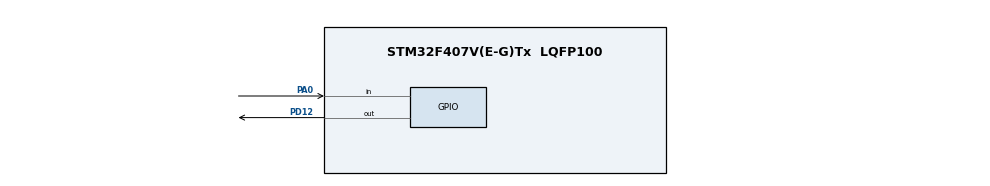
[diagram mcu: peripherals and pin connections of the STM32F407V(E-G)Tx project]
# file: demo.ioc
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Mcu.Family=STM32F4
Mcu.Name=STM32F407V(E-G)Tx
Mcu.Package=LQFP100
NVIC.PriorityGroup=NVIC_PRIORITYGROUP_4
PA0-WKUP.Signal=GPIO_Input
PD12.Signal=GPIO_Output
ProjectManager.HeapSize=0x200
ProjectManager.StackSize=0x400
ProjectManager.TargetToolchain=TrueSTUDIO
RCC.48MHZClocksFreq_Value=84000000
RCC.AHBFreq_Value=168000000
RCC.APB1CLKDivider=RCC_HCLK_DIV4
RCC.APB1Freq_Value=42000000
RCC.APB1TimFreq_Value=84000000
RCC.APB2CLKDivider=RCC_HCLK_DIV4
RCC.APB2Freq_Value=42000000
RCC.APB2TimFreq_Value=84000000
RCC.CortexFreq_Value=168000000
RCC.HCLKFreq_Value=168000000
RCC.HSE_VALUE=25000000
RCC.HSI_VALUE=16000000
RCC.LSE_VALUE=32768
RCC.PLLM=8
RCC.PLLN=168
RCC.SYSCLKFreq_VALUE=168000000
RCC.SYSCLKSource=RCC_SYSCLKSOURCE_PLLCLK
RCC.VCOOutputFreq_Value=336000000
board=demo

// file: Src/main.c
/**
  ******************************************************************************
  * File Name          : main.c
  * Description        : Main program body
  ******************************************************************************
  ** This notice applies to any and all portions of this file
  * that are not between comment pairs USER CODE BEGIN and
  * USER CODE END. Other portions of this file, whether
  * inserted by the user or by software development tools
  * are owned by their respective copyright owners.
  *
  * COPYRIGHT(c) 2018 STMicroelectronics
  *
  * Redistribution and use in source and binary forms, with or without modification,
  * are permitted provided that the following conditions are met:
  *   1. Redistributions of source code must retain the above copyright notice,
  *      this list of conditions and the following disclaimer.
  *   2. Redistributions in binary form must reproduce the above copyright notice,
  *      this list of conditions and the following disclaimer in the documentation
  *      and/or other materials provided with the distribution.
  *   3. Neither the name of STMicroelectronics nor the names of its contributors
  *      may be used to endorse or promote products derived from this software
  *      without specific prior written permission.
  *
  * THIS SOFTWARE IS PROVIDED BY THE COPYRIGHT HOLDERS AND CONTRIBUTORS "AS IS"
  * AND ANY EXPRESS OR IMPLIED WARRANTIES, INCLUDING, BUT NOT LIMITED TO, THE
  * IMPLIED WARRANTIES OF MERCHANTABILITY AND FITNESS FOR A PARTICULAR PURPOSE ARE
  * DISCLAIMED. IN NO EVENT SHALL THE COPYRIGHT HOLDER OR CONTRIBUTORS BE LIABLE
  * FOR ANY DIRECT, INDIRECT, INCIDENTAL, SPECIAL, EXEMPLARY, OR CONSEQUENTIAL
  * DAMAGES (INCLUDING, BUT NOT LIMITED TO, PROCUREMENT OF SUBSTITUTE GOODS OR
  * SERVICES; LOSS OF USE, DATA, OR PROFITS; OR BUSINESS INTERRUPTION) HOWEVER
  * CAUSED AND ON ANY THEORY OF LIABILITY, WHETHER IN CONTRACT, STRICT LIABILITY,
  * OR TORT (INCLUDING NEGLIGENCE OR OTHERWISE) ARISING IN ANY WAY OUT OF THE USE
  * OF THIS SOFTWARE, EVEN IF ADVISED OF THE POSSIBILITY OF SUCH DAMAGE.
  *
  ******************************************************************************
  */

#include "main.h"
#include "stm32f4xx_hal.h"

/* USER CODE BEGIN PV */
/* Private variables ---------------------------------------------------------*/

/* USER CODE END PV */

void SystemClock_Config(void);
static void MX_GPIO_Init(void);

/* USER CODE BEGIN PFP */
/* Private function prototypes -----------------------------------------------*/

/* USER CODE END PFP */

/* USER CODE BEGIN 0 */

void delay(uint16_t time_delay)
{
	volatile int i=0;
    for( i=0; i<time_delay;i++)
    {

    }
}

int v_counter=1;
int v_toggle;
int v_dir=1;
/* USER CODE END 0 */

int main(void)
{

  /* MCU Configuration----------------------------------------------------------*/

  /* Reset of all peripherals, Initializes the Flash interface and the Systick. */
  HAL_Init();

  /* Configure the system clock */
  SystemClock_Config();

  /* Initialize all configured peripherals */
  MX_GPIO_Init();

  /* Infinite loop */
  while (1)
  {

  /* USER CODE BEGIN 3 */
	 //// HAL_GPIO_TogglePin(GPIOD, GPIO_PIN_12);
		 // delay(599);
	  if(HAL_GPIO_ReadPin(GPIOA, GPIO_PIN_0))
	  {
		v_toggle=1;
	  }
	  else if(v_toggle)
	  {
		  // HAL_Delay(1000);
		   if(v_counter>8 || v_counter<2)
		   {
			   v_dir=-(v_dir);
		   }
		   v_counter= v_counter + v_dir;
		   v_toggle=0;
	  }

		 HAL_GPIO_WritePin(GPIOD, GPIO_PIN_12,GPIO_PIN_SET);
		 		  delay(119*(v_counter));
			  HAL_GPIO_WritePin(GPIOD, GPIO_PIN_12,GPIO_PIN_RESET);
			  delay(119*(10-v_counter));
  }
  /* USER CODE END 3 */

}

/** System Clock Configuration
*/
void SystemClock_Config(void)
{

  RCC_OscInitTypeDef RCC_OscInitStruct;
  RCC_ClkInitTypeDef RCC_ClkInitStruct;

    /**Configure the main internal regulator output voltage
    */
  __HAL_RCC_PWR_CLK_ENABLE();

  __HAL_PWR_VOLTAGESCALING_CONFIG(PWR_REGULATOR_VOLTAGE_SCALE1);

    /**Initializes the CPU, AHB and APB busses clocks
    */
  RCC_OscInitStruct.OscillatorType = RCC_OSCILLATORTYPE_HSI;
  RCC_OscInitStruct.HSIState = RCC_HSI_ON;
  RCC_OscInitStruct.HSICalibrationValue = 16;
  RCC_OscInitStruct.PLL.PLLState = RCC_PLL_ON;
  RCC_OscInitStruct.PLL.PLLSource = RCC_PLLSOURCE_HSI;
  RCC_OscInitStruct.PLL.PLLM = 8;
  RCC_OscInitStruct.PLL.PLLN = 168;
  RCC_OscInitStruct.PLL.PLLP = RCC_PLLP_DIV2;
  RCC_OscInitStruct.PLL.PLLQ = 4;
  if (HAL_RCC_OscConfig(&RCC_OscInitStruct) != HAL_OK)
  {
    _Error_Handler(__FILE__, __LINE__);
  }

    /**Initializes the CPU, AHB and APB busses clocks
    */
  RCC_ClkInitStruct.ClockType = RCC_CLOCKTYPE_HCLK|RCC_CLOCKTYPE_SYSCLK
                              |RCC_CLOCKTYPE_PCLK1|RCC_CLOCKTYPE_PCLK2;
  RCC_ClkInitStruct.SYSCLKSource = RCC_SYSCLKSOURCE_PLLCLK;
  RCC_ClkInitStruct.AHBCLKDivider = RCC_SYSCLK_DIV1;
  RCC_ClkInitStruct.APB1CLKDivider = RCC_HCLK_DIV8;
  RCC_ClkInitStruct.APB2CLKDivider = RCC_HCLK_DIV4;

  if (HAL_RCC_ClockConfig(&RCC_ClkInitStruct, FLASH_LATENCY_5) != HAL_OK)
  {
    _Error_Handler(__FILE__, __LINE__);
  }

    /**Configure the Systick interrupt time
    */
  HAL_SYSTICK_Config(HAL_RCC_GetHCLKFreq()/1000);

    /**Configure the Systick
    */
  HAL_SYSTICK_CLKSourceConfig(SYSTICK_CLKSOURCE_HCLK);

  /* SysTick_IRQn interrupt configuration */
  HAL_NVIC_SetPriority(SysTick_IRQn, 0, 0);
}

/** Configure pins as
        * Analog
        * Input
        * Output
        * EVENT_OUT
        * EXTI
*/
static void MX_GPIO_Init(void)
{

  GPIO_InitTypeDef GPIO_InitStruct;

  /* GPIO Ports Clock Enable */
  __HAL_RCC_GPIOA_CLK_ENABLE();
  __HAL_RCC_GPIOD_CLK_ENABLE();

  /*Configure GPIO pin Output Level */
  HAL_GPIO_WritePin(GPIOD, GPIO_PIN_12, GPIO_PIN_RESET);

  /*Configure GPIO pin : PA0 */
  GPIO_InitStruct.Pin = GPIO_PIN_0;
  GPIO_InitStruct.Mode = GPIO_MODE_INPUT;
  GPIO_InitStruct.Pull = GPIO_NOPULL;
  HAL_GPIO_Init(GPIOA, &GPIO_InitStruct);

  /*Configure GPIO pin : PD12 */
  GPIO_InitStruct.Pin = GPIO_PIN_12;
  GPIO_InitStruct.Mode = GPIO_MODE_OUTPUT_PP;
  GPIO_InitStruct.Pull = GPIO_NOPULL;
  GPIO_InitStruct.Speed = GPIO_SPEED_FREQ_LOW;
  HAL_GPIO_Init(GPIOD, &GPIO_InitStruct);

}

void _Error_Handler(char * file, int line)
{
  while(1)
  {
  }
}

/************************ (C) COPYRIGHT STMicroelectronics *****END OF FILE****/
